One B-rep face of a CAD part: STEP entity #1472.
In plain terms, the planar face has unit normal (0, 0, 1).
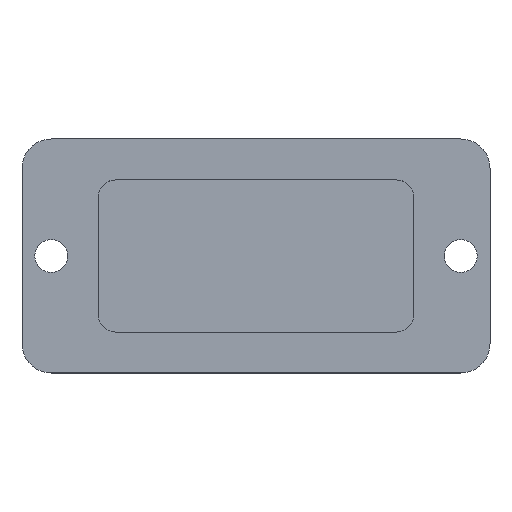
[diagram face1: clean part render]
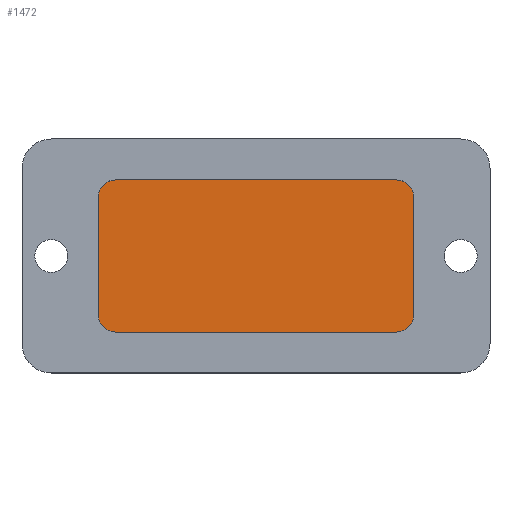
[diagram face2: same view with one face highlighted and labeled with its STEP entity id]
Its self-contained STEP definition (entity closure, numbers rounded to 3 decimals):
#653 = CYLINDRICAL_SURFACE('',#654,1.5);
#654 = AXIS2_PLACEMENT_3D('',#655,#656,#657);
#655 = CARTESIAN_POINT('',(12.,-5.,-0.1));
#656 = DIRECTION('',(0.,0.,1.));
#657 = DIRECTION('',(0.,-1.,0.));
#680 = PLANE('',#681);
#681 = AXIS2_PLACEMENT_3D('',#682,#683,#684);
#682 = CARTESIAN_POINT('',(-13.5,-6.5,-0.1));
#683 = DIRECTION('',(0.,1.,0.));
#684 = DIRECTION('',(1.,0.,0.));
#708 = CYLINDRICAL_SURFACE('',#709,1.5);
#709 = AXIS2_PLACEMENT_3D('',#710,#711,#712);
#710 = CARTESIAN_POINT('',(-12.,-5.,-0.1));
#711 = DIRECTION('',(0.,0.,1.));
#712 = DIRECTION('',(0.,-1.,0.));
#735 = PLANE('',#736);
#736 = AXIS2_PLACEMENT_3D('',#737,#738,#739);
#737 = CARTESIAN_POINT('',(-13.5,6.5,-0.1));
#738 = DIRECTION('',(1.,0.,-0.));
#739 = DIRECTION('',(0.,-1.,0.));
#763 = CYLINDRICAL_SURFACE('',#764,1.5);
#764 = AXIS2_PLACEMENT_3D('',#765,#766,#767);
#765 = CARTESIAN_POINT('',(-12.,5.,-0.1));
#766 = DIRECTION('',(0.,0.,1.));
#767 = DIRECTION('',(-0.,1.,0.));
#790 = PLANE('',#791);
#791 = AXIS2_PLACEMENT_3D('',#792,#793,#794);
#792 = CARTESIAN_POINT('',(13.5,6.5,-0.1));
#793 = DIRECTION('',(0.,-1.,0.));
#794 = DIRECTION('',(-1.,0.,0.));
#818 = CYLINDRICAL_SURFACE('',#819,1.5);
#819 = AXIS2_PLACEMENT_3D('',#820,#821,#822);
#820 = CARTESIAN_POINT('',(12.,5.,-0.1));
#821 = DIRECTION('',(0.,0.,1.));
#822 = DIRECTION('',(1.,0.,-0.));
#843 = PLANE('',#844);
#844 = AXIS2_PLACEMENT_3D('',#845,#846,#847);
#845 = CARTESIAN_POINT('',(13.5,-6.5,-0.1));
#846 = DIRECTION('',(-1.,0.,0.));
#847 = DIRECTION('',(0.,1.,0.));
#1084 = VERTEX_POINT('',#1085);
#1085 = CARTESIAN_POINT('',(12.,-6.5,0.4));
#1106 = EDGE_CURVE('',#1084,#1107,#1109,.T.);
#1107 = VERTEX_POINT('',#1108);
#1108 = CARTESIAN_POINT('',(13.5,-5.,0.4));
#1109 = SURFACE_CURVE('',#1110,(#1115,#1122),.PCURVE_S1.);
#1110 = CIRCLE('',#1111,1.5);
#1111 = AXIS2_PLACEMENT_3D('',#1112,#1113,#1114);
#1112 = CARTESIAN_POINT('',(12.,-5.,0.4));
#1113 = DIRECTION('',(0.,0.,1.));
#1114 = DIRECTION('',(0.,-1.,0.));
#1115 = PCURVE('',#653,#1116);
#1116 = DEFINITIONAL_REPRESENTATION('',(#1117),#1121);
#1117 = LINE('',#1118,#1119);
#1118 = CARTESIAN_POINT('',(0.,0.5));
#1119 = VECTOR('',#1120,1.);
#1120 = DIRECTION('',(1.,0.));
#1121 = ( GEOMETRIC_REPRESENTATION_CONTEXT(2) 
PARAMETRIC_REPRESENTATION_CONTEXT() REPRESENTATION_CONTEXT('2D SPACE',''
  ) );
#1122 = PCURVE('',#1123,#1128);
#1123 = PLANE('',#1124);
#1124 = AXIS2_PLACEMENT_3D('',#1125,#1126,#1127);
#1125 = CARTESIAN_POINT('',(0.,0.,0.4));
#1126 = DIRECTION('',(0.,0.,1.));
#1127 = DIRECTION('',(1.,0.,-0.));
#1128 = DEFINITIONAL_REPRESENTATION('',(#1129),#1133);
#1129 = CIRCLE('',#1130,1.5);
#1130 = AXIS2_PLACEMENT_2D('',#1131,#1132);
#1131 = CARTESIAN_POINT('',(12.,-5.));
#1132 = DIRECTION('',(0.,-1.));
#1133 = ( GEOMETRIC_REPRESENTATION_CONTEXT(2) 
PARAMETRIC_REPRESENTATION_CONTEXT() REPRESENTATION_CONTEXT('2D SPACE',''
  ) );
#1161 = EDGE_CURVE('',#1084,#1162,#1164,.T.);
#1162 = VERTEX_POINT('',#1163);
#1163 = CARTESIAN_POINT('',(-12.,-6.5,0.4));
#1164 = SURFACE_CURVE('',#1165,(#1169,#1175),.PCURVE_S1.);
#1165 = LINE('',#1166,#1167);
#1166 = CARTESIAN_POINT('',(-6.75,-6.5,0.4));
#1167 = VECTOR('',#1168,1.);
#1168 = DIRECTION('',(-1.,0.,0.));
#1169 = PCURVE('',#680,#1170);
#1170 = DEFINITIONAL_REPRESENTATION('',(#1171),#1174);
#1171 = B_SPLINE_CURVE_WITH_KNOTS('',1,(#1172,#1173),.UNSPECIFIED.,.F.,
  .F.,(2,2),(-18.75,5.25),.PIECEWISE_BEZIER_KNOTS.);
#1172 = CARTESIAN_POINT('',(25.5,-0.5));
#1173 = CARTESIAN_POINT('',(1.5,-0.5));
#1174 = ( GEOMETRIC_REPRESENTATION_CONTEXT(2) 
PARAMETRIC_REPRESENTATION_CONTEXT() REPRESENTATION_CONTEXT('2D SPACE',''
  ) );
#1175 = PCURVE('',#1123,#1176);
#1176 = DEFINITIONAL_REPRESENTATION('',(#1177),#1180);
#1177 = B_SPLINE_CURVE_WITH_KNOTS('',1,(#1178,#1179),.UNSPECIFIED.,.F.,
  .F.,(2,2),(-18.75,5.25),.PIECEWISE_BEZIER_KNOTS.);
#1178 = CARTESIAN_POINT('',(12.,-6.5));
#1179 = CARTESIAN_POINT('',(-12.,-6.5));
#1180 = ( GEOMETRIC_REPRESENTATION_CONTEXT(2) 
PARAMETRIC_REPRESENTATION_CONTEXT() REPRESENTATION_CONTEXT('2D SPACE',''
  ) );
#1208 = VERTEX_POINT('',#1209);
#1209 = CARTESIAN_POINT('',(13.5,5.,0.4));
#1230 = EDGE_CURVE('',#1208,#1107,#1231,.T.);
#1231 = SURFACE_CURVE('',#1232,(#1236,#1242),.PCURVE_S1.);
#1232 = LINE('',#1233,#1234);
#1233 = CARTESIAN_POINT('',(13.5,-3.25,0.4));
#1234 = VECTOR('',#1235,1.);
#1235 = DIRECTION('',(0.,-1.,0.));
#1236 = PCURVE('',#843,#1237);
#1237 = DEFINITIONAL_REPRESENTATION('',(#1238),#1241);
#1238 = B_SPLINE_CURVE_WITH_KNOTS('',1,(#1239,#1240),.UNSPECIFIED.,.F.,
  .F.,(2,2),(-8.25,1.75),.PIECEWISE_BEZIER_KNOTS.);
#1239 = CARTESIAN_POINT('',(11.5,-0.5));
#1240 = CARTESIAN_POINT('',(1.5,-0.5));
#1241 = ( GEOMETRIC_REPRESENTATION_CONTEXT(2) 
PARAMETRIC_REPRESENTATION_CONTEXT() REPRESENTATION_CONTEXT('2D SPACE',''
  ) );
#1242 = PCURVE('',#1123,#1243);
#1243 = DEFINITIONAL_REPRESENTATION('',(#1244),#1247);
#1244 = B_SPLINE_CURVE_WITH_KNOTS('',1,(#1245,#1246),.UNSPECIFIED.,.F.,
  .F.,(2,2),(-8.25,1.75),.PIECEWISE_BEZIER_KNOTS.);
#1245 = CARTESIAN_POINT('',(13.5,5.));
#1246 = CARTESIAN_POINT('',(13.5,-5.));
#1247 = ( GEOMETRIC_REPRESENTATION_CONTEXT(2) 
PARAMETRIC_REPRESENTATION_CONTEXT() REPRESENTATION_CONTEXT('2D SPACE',''
  ) );
#1255 = EDGE_CURVE('',#1256,#1162,#1258,.T.);
#1256 = VERTEX_POINT('',#1257);
#1257 = CARTESIAN_POINT('',(-13.5,-5.,0.4));
#1258 = SURFACE_CURVE('',#1259,(#1264,#1271),.PCURVE_S1.);
#1259 = CIRCLE('',#1260,1.5);
#1260 = AXIS2_PLACEMENT_3D('',#1261,#1262,#1263);
#1261 = CARTESIAN_POINT('',(-12.,-5.,0.4));
#1262 = DIRECTION('',(0.,0.,1.));
#1263 = DIRECTION('',(0.,-1.,0.));
#1264 = PCURVE('',#708,#1265);
#1265 = DEFINITIONAL_REPRESENTATION('',(#1266),#1270);
#1266 = LINE('',#1267,#1268);
#1267 = CARTESIAN_POINT('',(-6.283,0.5));
#1268 = VECTOR('',#1269,1.);
#1269 = DIRECTION('',(1.,-0.));
#1270 = ( GEOMETRIC_REPRESENTATION_CONTEXT(2) 
PARAMETRIC_REPRESENTATION_CONTEXT() REPRESENTATION_CONTEXT('2D SPACE',''
  ) );
#1271 = PCURVE('',#1123,#1272);
#1272 = DEFINITIONAL_REPRESENTATION('',(#1273),#1277);
#1273 = CIRCLE('',#1274,1.5);
#1274 = AXIS2_PLACEMENT_2D('',#1275,#1276);
#1275 = CARTESIAN_POINT('',(-12.,-5.));
#1276 = DIRECTION('',(0.,-1.));
#1277 = ( GEOMETRIC_REPRESENTATION_CONTEXT(2) 
PARAMETRIC_REPRESENTATION_CONTEXT() REPRESENTATION_CONTEXT('2D SPACE',''
  ) );
#1305 = EDGE_CURVE('',#1208,#1306,#1308,.T.);
#1306 = VERTEX_POINT('',#1307);
#1307 = CARTESIAN_POINT('',(12.,6.5,0.4));
#1308 = SURFACE_CURVE('',#1309,(#1314,#1321),.PCURVE_S1.);
#1309 = CIRCLE('',#1310,1.5);
#1310 = AXIS2_PLACEMENT_3D('',#1311,#1312,#1313);
#1311 = CARTESIAN_POINT('',(12.,5.,0.4));
#1312 = DIRECTION('',(0.,0.,1.));
#1313 = DIRECTION('',(1.,0.,-0.));
#1314 = PCURVE('',#818,#1315);
#1315 = DEFINITIONAL_REPRESENTATION('',(#1316),#1320);
#1316 = LINE('',#1317,#1318);
#1317 = CARTESIAN_POINT('',(0.,0.5));
#1318 = VECTOR('',#1319,1.);
#1319 = DIRECTION('',(1.,0.));
#1320 = ( GEOMETRIC_REPRESENTATION_CONTEXT(2) 
PARAMETRIC_REPRESENTATION_CONTEXT() REPRESENTATION_CONTEXT('2D SPACE',''
  ) );
#1321 = PCURVE('',#1123,#1322);
#1322 = DEFINITIONAL_REPRESENTATION('',(#1323),#1327);
#1323 = CIRCLE('',#1324,1.5);
#1324 = AXIS2_PLACEMENT_2D('',#1325,#1326);
#1325 = CARTESIAN_POINT('',(12.,5.));
#1326 = DIRECTION('',(1.,0.));
#1327 = ( GEOMETRIC_REPRESENTATION_CONTEXT(2) 
PARAMETRIC_REPRESENTATION_CONTEXT() REPRESENTATION_CONTEXT('2D SPACE',''
  ) );
#1355 = EDGE_CURVE('',#1256,#1356,#1358,.T.);
#1356 = VERTEX_POINT('',#1357);
#1357 = CARTESIAN_POINT('',(-13.5,5.,0.4));
#1358 = SURFACE_CURVE('',#1359,(#1363,#1369),.PCURVE_S1.);
#1359 = LINE('',#1360,#1361);
#1360 = CARTESIAN_POINT('',(-13.5,3.25,0.4));
#1361 = VECTOR('',#1362,1.);
#1362 = DIRECTION('',(-0.,1.,0.));
#1363 = PCURVE('',#735,#1364);
#1364 = DEFINITIONAL_REPRESENTATION('',(#1365),#1368);
#1365 = B_SPLINE_CURVE_WITH_KNOTS('',1,(#1366,#1367),.UNSPECIFIED.,.F.,
  .F.,(2,2),(-8.25,1.75),.PIECEWISE_BEZIER_KNOTS.);
#1366 = CARTESIAN_POINT('',(11.5,-0.5));
#1367 = CARTESIAN_POINT('',(1.5,-0.5));
#1368 = ( GEOMETRIC_REPRESENTATION_CONTEXT(2) 
PARAMETRIC_REPRESENTATION_CONTEXT() REPRESENTATION_CONTEXT('2D SPACE',''
  ) );
#1369 = PCURVE('',#1123,#1370);
#1370 = DEFINITIONAL_REPRESENTATION('',(#1371),#1374);
#1371 = B_SPLINE_CURVE_WITH_KNOTS('',1,(#1372,#1373),.UNSPECIFIED.,.F.,
  .F.,(2,2),(-8.25,1.75),.PIECEWISE_BEZIER_KNOTS.);
#1372 = CARTESIAN_POINT('',(-13.5,-5.));
#1373 = CARTESIAN_POINT('',(-13.5,5.));
#1374 = ( GEOMETRIC_REPRESENTATION_CONTEXT(2) 
PARAMETRIC_REPRESENTATION_CONTEXT() REPRESENTATION_CONTEXT('2D SPACE',''
  ) );
#1402 = VERTEX_POINT('',#1403);
#1403 = CARTESIAN_POINT('',(-12.,6.5,0.4));
#1424 = EDGE_CURVE('',#1402,#1306,#1425,.T.);
#1425 = SURFACE_CURVE('',#1426,(#1430,#1436),.PCURVE_S1.);
#1426 = LINE('',#1427,#1428);
#1427 = CARTESIAN_POINT('',(6.75,6.5,0.4));
#1428 = VECTOR('',#1429,1.);
#1429 = DIRECTION('',(1.,0.,-0.));
#1430 = PCURVE('',#790,#1431);
#1431 = DEFINITIONAL_REPRESENTATION('',(#1432),#1435);
#1432 = B_SPLINE_CURVE_WITH_KNOTS('',1,(#1433,#1434),.UNSPECIFIED.,.F.,
  .F.,(2,2),(-18.75,5.25),.PIECEWISE_BEZIER_KNOTS.);
#1433 = CARTESIAN_POINT('',(25.5,-0.5));
#1434 = CARTESIAN_POINT('',(1.5,-0.5));
#1435 = ( GEOMETRIC_REPRESENTATION_CONTEXT(2) 
PARAMETRIC_REPRESENTATION_CONTEXT() REPRESENTATION_CONTEXT('2D SPACE',''
  ) );
#1436 = PCURVE('',#1123,#1437);
#1437 = DEFINITIONAL_REPRESENTATION('',(#1438),#1441);
#1438 = B_SPLINE_CURVE_WITH_KNOTS('',1,(#1439,#1440),.UNSPECIFIED.,.F.,
  .F.,(2,2),(-18.75,5.25),.PIECEWISE_BEZIER_KNOTS.);
#1439 = CARTESIAN_POINT('',(-12.,6.5));
#1440 = CARTESIAN_POINT('',(12.,6.5));
#1441 = ( GEOMETRIC_REPRESENTATION_CONTEXT(2) 
PARAMETRIC_REPRESENTATION_CONTEXT() REPRESENTATION_CONTEXT('2D SPACE',''
  ) );
#1449 = EDGE_CURVE('',#1402,#1356,#1450,.T.);
#1450 = SURFACE_CURVE('',#1451,(#1456,#1463),.PCURVE_S1.);
#1451 = CIRCLE('',#1452,1.5);
#1452 = AXIS2_PLACEMENT_3D('',#1453,#1454,#1455);
#1453 = CARTESIAN_POINT('',(-12.,5.,0.4));
#1454 = DIRECTION('',(0.,0.,1.));
#1455 = DIRECTION('',(-0.,1.,0.));
#1456 = PCURVE('',#763,#1457);
#1457 = DEFINITIONAL_REPRESENTATION('',(#1458),#1462);
#1458 = LINE('',#1459,#1460);
#1459 = CARTESIAN_POINT('',(0.,0.5));
#1460 = VECTOR('',#1461,1.);
#1461 = DIRECTION('',(1.,0.));
#1462 = ( GEOMETRIC_REPRESENTATION_CONTEXT(2) 
PARAMETRIC_REPRESENTATION_CONTEXT() REPRESENTATION_CONTEXT('2D SPACE',''
  ) );
#1463 = PCURVE('',#1123,#1464);
#1464 = DEFINITIONAL_REPRESENTATION('',(#1465),#1469);
#1465 = CIRCLE('',#1466,1.5);
#1466 = AXIS2_PLACEMENT_2D('',#1467,#1468);
#1467 = CARTESIAN_POINT('',(-12.,5.));
#1468 = DIRECTION('',(0.,1.));
#1469 = ( GEOMETRIC_REPRESENTATION_CONTEXT(2) 
PARAMETRIC_REPRESENTATION_CONTEXT() REPRESENTATION_CONTEXT('2D SPACE',''
  ) );
#1472 = ADVANCED_FACE('',(#1473),#1123,.T.);
#1473 = FACE_BOUND('',#1474,.T.);
#1474 = EDGE_LOOP('',(#1475,#1476,#1477,#1478,#1479,#1480,#1481,#1482));
#1475 = ORIENTED_EDGE('',*,*,#1161,.F.);
#1476 = ORIENTED_EDGE('',*,*,#1106,.T.);
#1477 = ORIENTED_EDGE('',*,*,#1230,.F.);
#1478 = ORIENTED_EDGE('',*,*,#1305,.T.);
#1479 = ORIENTED_EDGE('',*,*,#1424,.F.);
#1480 = ORIENTED_EDGE('',*,*,#1449,.T.);
#1481 = ORIENTED_EDGE('',*,*,#1355,.F.);
#1482 = ORIENTED_EDGE('',*,*,#1255,.T.);
